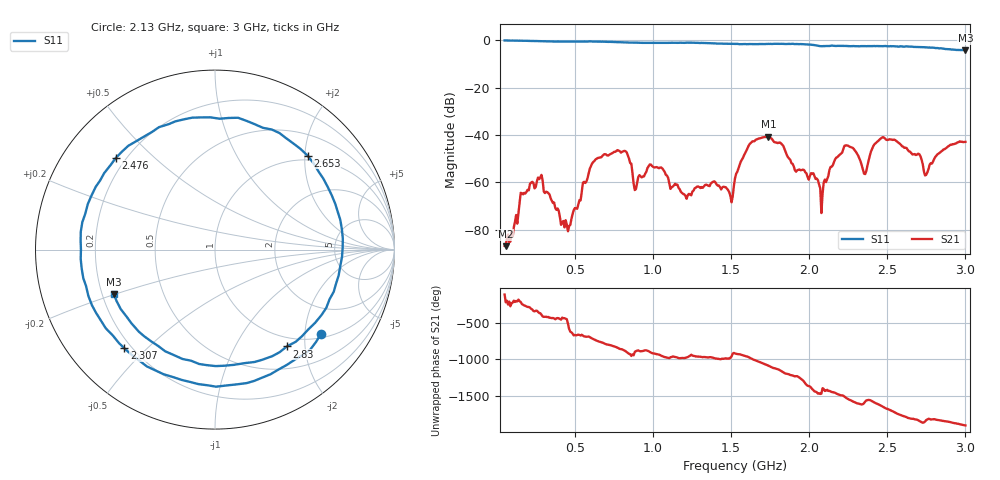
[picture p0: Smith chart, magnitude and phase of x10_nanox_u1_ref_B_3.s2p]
! nanovna_capture.py 2026-10-18T20:33:56+0900
! NanoVNA-F_V2 fw 0.6.0 SN 4A3639384505514B
! cal: load open short thru cal'ed  over 50000000-3000000000 Hz, 201 points
! points 401, avg 4
! S21: port1 = green ~10 mm H loop (flat, tape), port2 = GSM antenna; genuine Nano X u1 at position B, placement 3
# HZ S RI R 50
! S12 and S22 are not measured (written as 0)
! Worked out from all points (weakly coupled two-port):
!   401 points, 50 MHz to 3 GHz, reference 50 ohm
!   highest |S21| = -40.70 dB at 1.739 GHz (marker M1); lowest = -86.9 dB at 57.38 MHz (marker M2)
!   lowest |S11| = -4.2 dB at 3 GHz (marker M3), VSWR 4.20, Z = 12.4 - j9.94 ohm
!   |S11| at or under -10 dB: nowhere
!   S12 and S22 are empty: the file has one direction only
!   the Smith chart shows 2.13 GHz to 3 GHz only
!   S11 on the Smith chart (normalised r, x): 2.13 GHz: 1.11, -2.41; 2.307 GHz: 0.17, -0.43; 2.476 GHz: 0.16, +0.38; 2.653 GHz: 0.90, +2.06; 2.83 GHz: 0.84, -1.66; 3 GHz: 0.25, -0.20
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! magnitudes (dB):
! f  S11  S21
! 50 MHz  -0.1  -86.8
! 57.38 MHz  -0.1  -86.9
! 271.2 MHz  -0.4  -58.6
! 448.2 MHz  -0.6  -77.9
! 544.1 MHz  -0.6  -63.7
! 765.4 MHz  -0.8  -46.7
! 890.8 MHz  -1.0  -62.8
! 1.038 GHz  -1.2  -54.0
! 1.208 GHz  -1.1  -65.7
! 1.525 GHz  -1.6  -58.3
! 1.739 GHz  -1.5  -40.7
! 2.019 GHz  -1.9  -56.4
! 2.078 GHz  -2.5  -73.0
! 2.13 GHz  -2.4  -54.7
! 2.307 GHz  -2.5  -48.0
! 2.358 GHz  -2.5  -56.5
! 2.476 GHz  -2.5  -40.9
! 2.513 GHz  -2.6  -41.8
! 2.653 GHz  -2.7  -47.6
! 2.749 GHz  -3.0  -56.8
! 2.83 GHz  -3.5  -47.7
! 3 GHz  -4.2  -42.9
